VERSION 5.8 ;
BUSBITCHARS "[]" ;
DIVIDERCHAR "/" ;

UNITS
  DATABASE MICRONS 1000 ;
END UNITS

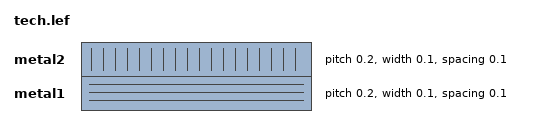
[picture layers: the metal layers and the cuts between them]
LAYER metal1
  TYPE ROUTING ;
  DIRECTION HORIZONTAL ;
  PITCH 0.20 ;
  WIDTH 0.10 ;
  SPACING 0.10 ;
END metal1

LAYER metal2
  TYPE ROUTING ;
  DIRECTION VERTICAL ;
  PITCH 0.20 ;
  WIDTH 0.10 ;
  SPACING 0.10 ;
END metal2

END LIBRARY
